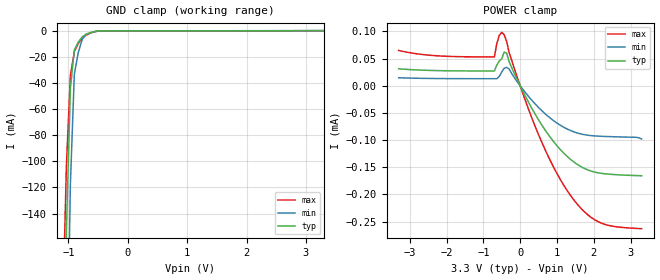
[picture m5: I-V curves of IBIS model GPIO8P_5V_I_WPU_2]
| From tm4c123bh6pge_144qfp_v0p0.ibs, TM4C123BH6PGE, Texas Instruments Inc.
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|   Model Cell GPIO8P_5V_I_WPU_2
[Model]   GPIO8P_5V_I_WPU_2
Model_type   Input
Polarity   Non-Inverting
Vinl =  0.8
Vinh =  2
C_comp   4.711578p   4.034737p   5.423069p
[Model Spec]
Vinl   0.8   0.8   0.8
Vinh   2   2   2
[Temperature Range]   25   125   -40
[Voltage Range]   3.3   2.97   3.63
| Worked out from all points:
|   GND clamp passes 1 mA (typ) near -0.58 V on its own axis
| Nom Voltages:
|   VDDC=1.2, VDD=3.3, GND=0
| Min Voltages:
|   VDDC=1.08, VDD=2.97, GND=0
| Max Voltages:
|   VDDC=1.32, VDD=3.63, GND=0
[POWER_clamp]
|   voltage   I(typ)   I(min)   I(max)
-3.3V     31.22uA    14.76uA    64.95uA
-700mV    27.24uA    13.03uA    53.12uA
-566.7mV  45.54uA    17.17uA    92.88uA
-500mV    49.58uA    25.46uA    98.23uA
-433.3mV  61.99uA    32.06uA    93.82uA
-366.7mV  60.27uA    33.88uA    81.56uA
-33.33mV  4.744uA    3.118uA    6.661uA
500mV     -62.72uA   -39.99uA   -89.98uA
900mV     -102.1uA   -63.88uA   -148.7uA
1.367V    -135.3uA   -82.34uA   -201.6uA
2.1V      -160uA     -92.63uA   -249.6uA
3.3V      -165.6uA   -97.93uA   -263uA
[GND_clamp]
|   voltage   I(typ)   I(min)   I(max)
-3.3V     -16.3A     -15.26A    -17.13A
-1.1V     -340.4mA   -570.5mA   -222.8mA
-1.033V   -152.7mA   -296.8mA   -103.3mA
-966.7mV  -44.18mA   -117.7mA   -34.41mA
-900mV    -14.77mA   -33.13mA   -16.15mA
-833.3mV  -8.769mA   -16.69mA   -9.878mA
-766.7mV  -4.756mA   -6.569mA   -5.651mA
-700mV    -2.732mA   -2.771mA   -3.471mA
-566.7mV  -805.7uA   -794.8uA   -943uA
-433.3mV  -213.6uA   -180.7uA   -296.9uA
3.3V      655.7pA    35.93uA    -61.41uA
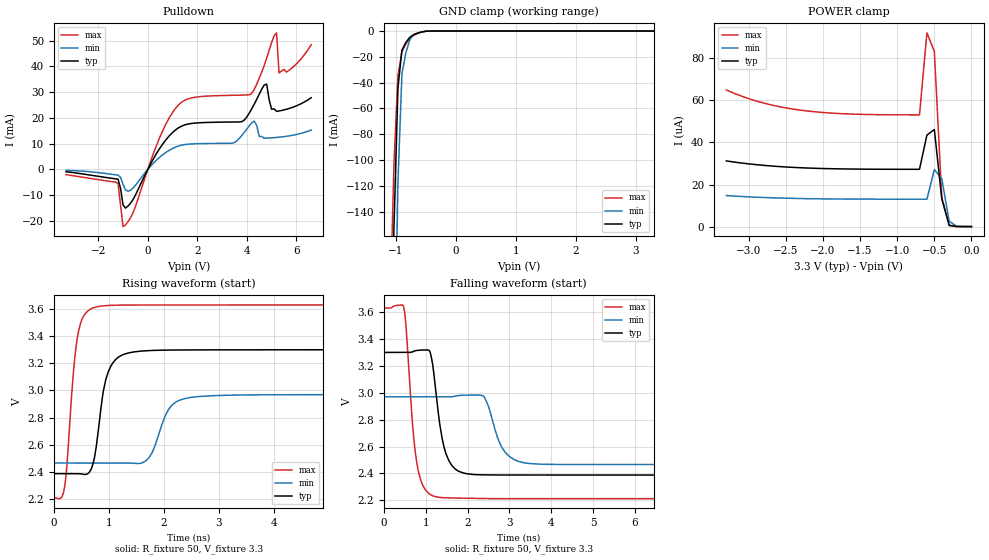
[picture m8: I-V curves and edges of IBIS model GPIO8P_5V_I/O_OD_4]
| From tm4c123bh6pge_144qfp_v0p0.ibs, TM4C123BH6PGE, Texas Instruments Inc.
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|   Model Cell GPIO8P_5V_I/O_OD_4
[Model]   GPIO8P_5V_I/O_OD_4
Model_type   I/O_open_drain
Polarity   Inverting
Enable   Active-Low
Vinl =  0.8
Vinh =  2
Cref =  15.0000pF
Rref =  100.0000M
Vref =  0V
Vmeas =  1.65
C_comp   4.711578p   4.034737p   5.423069p
[Model Spec]
Vinl   0.8   0.8   0.8
Vinh   2   2   2
[Temperature Range]   25   125   -40
[Voltage Range]   3.3   2.97   3.63
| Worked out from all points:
|   slope of the pulldown table from 0 to 0.495 V, typ, clamps not added: 59.3 ohm
|   GND clamp passes 1 mA (typ) near -0.59 V on its own axis
|   rising waveform, R_fixture 50, V_fixture 3.3: 20-80 % time 208ps typ, 290ps min, 166ps max; typ from 2.39 V to 3.3 V
|   falling waveform, R_fixture 50, V_fixture 3.3: 20-80 % time 259ps typ, 347ps min, 216ps max; typ from 3.3 V to 2.39 V
| Nom Voltages:
|   VDDC=1.2, VDD=3.3, GND=0
| Min Voltages:
|   VDDC=1.08, VDD=2.97, GND=0
| Max Voltages:
|   VDDC=1.32, VDD=3.63, GND=0
[POWER_clamp]
|   voltage   I(typ)   I(min)   I(max)
-3.3V     31.22uA    14.76uA    64.95uA
-3.1V     30.25uA    14.33uA    62.09uA
-2.8V     29.13uA    13.84uA    58.77uA
-2.3V     27.98uA    13.34uA    55.36uA
-1.7V     27.4uA     13.1uA     53.62uA
-700mV    27.24uA    13.03uA    53.12uA
-600mV    43.52uA    13.03uA    92.14uA
-500mV    46.16uA    27.05uA    83.3uA
-400mV    13.21uA    22.74uA    13.98uA
-300mV    630.7nA    2.501uA    480.9nA
-200mV    23.21nA    190.8nA    10.65nA
0V        660.4pA    10.19nA    564.9pA
[Pulldown]
|   voltage   I(typ)   I(min)   I(max)
-3.3V     -901.6uA   -384.4uA   -2.013mA
-1.2V     -3.786mA   -2.218mA   -5.418mA
-1V       -13.75mA   -5.79mA    -22.19mA
-700mV    -13.13mA   -8.08mA    -18.83mA
1.3V      16.5mA     9.253mA    25.59mA
3.5V      18.42mA    10.46mA    28.8mA
4.2V      23.61mA    18.14mA    29.55mA
4.8V      33.14mA    12.18mA    43.24mA
5V        23.36mA    12.28mA    49.33mA
5.2V      22.53mA    12.43mA    53.05mA
5.3V      22.7mA     12.52mA    37.48mA
6.6V      27.85mA    15.27mA    48.43mA
[GND_clamp]
|   voltage   I(typ)   I(min)   I(max)
-3.3V     -16.3A     -15.26A    -17.13A
-1.1V     -340.4mA   -570.5mA   -222.8mA
-1.033V   -152.7mA   -296.8mA   -103.3mA
-966.7mV  -44.18mA   -117.7mA   -34.4mA
-900mV    -14.77mA   -33.12mA   -16.14mA
-833.3mV  -8.752mA   -16.68mA   -9.833mA
-766.7mV  -4.716mA   -6.551mA   -5.563mA
-700mV    -2.657mA   -2.741mA   -3.333mA
-566.7mV  -672.8uA   -727.2uA   -724.4uA
-433.3mV  -51.87uA   -90.8uA    -37.79uA
3.3V      660.4pA    5.308uA    422.7pA
[Ramp]
| variable   typ   min   max
dV/dt_f  0.5587141/0.26045662n 0.31023858/0.352185n  0.86504244/0.21760119n
dV/dt_r 0.72667108/0.52198411n 0.45768162/0.8533017n   1.027789/0.38356156n
R_load = 50
[Rising Waveform]
R_fixture = 50
V_fixture = 3.3
V_fixture_min = 2.97
V_fixture_max = 3.63
|   time   V(typ)   V(min)   V(max)
0s        2.388V     2.466V     2.211V
198.6ps   2.388V     2.466V     2.297V
375ps     2.388V     2.466V     3.219V
457.4ps   2.387V     2.466V     3.451V
692.2ps   2.433V     2.466V     3.604V
849.4ps   2.842V     2.466V     3.621V
982.8ps   3.13V      2.466V     3.626V
1.222ns   3.257V     2.466V     3.629V
2.761ns   3.299V     2.959V     3.63V
20.01ns   3.3V       2.97V      3.63V
[Falling Waveform]
R_fixture = 50
V_fixture = 3.3
V_fixture_min = 2.97
V_fixture_max = 3.63
|   time   V(typ)   V(min)   V(max)
0s        3.3V       2.97V      3.63V
471.4ps   3.3V       2.97V      3.639V
817.4ps   3.316V     2.97V      2.422V
1.099ns   3.305V     2.97V      2.245V
1.273ns   2.918V     2.97V      2.224V
1.545ns   2.499V     2.97V      2.218V
2.126ns   2.392V     2.982V     2.214V
2.889ns   2.388V     2.56V      2.212V
3.475ns   2.388V     2.474V     2.212V
20.01ns   2.388V     2.466V     2.212V
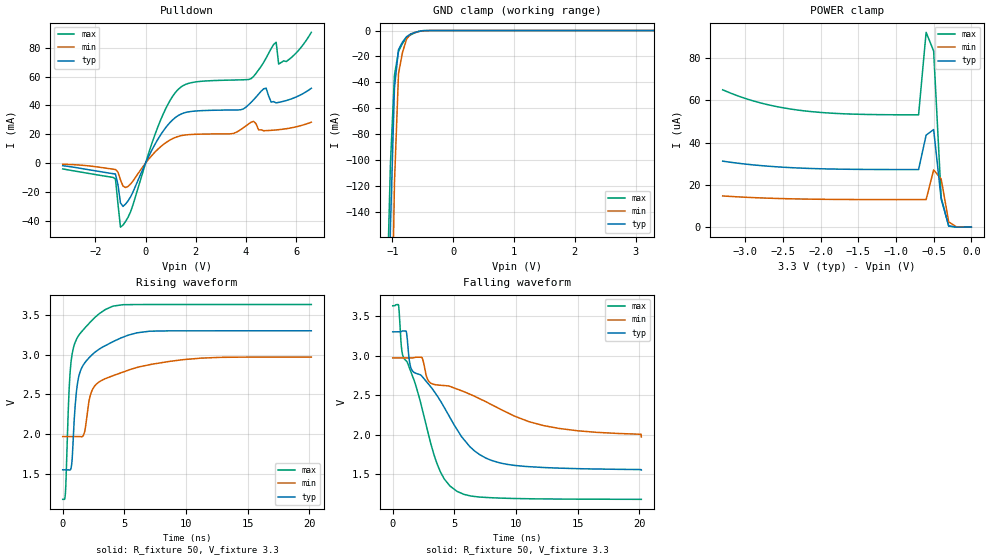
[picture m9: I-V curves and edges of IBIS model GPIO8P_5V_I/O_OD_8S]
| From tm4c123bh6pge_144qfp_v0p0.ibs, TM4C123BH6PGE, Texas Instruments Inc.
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|   Model Cell GPIO8P_5V_I/O_OD_8S
[Model]   GPIO8P_5V_I/O_OD_8S
Model_type   I/O_open_drain
Polarity   Inverting
Enable   Active-Low
Vinl =  0.8
Vinh =  2
Cref =  15.0000pF
Rref =  100.0000M
Vref =  0V
Vmeas =  1.65
C_comp   4.711578p   4.034737p   5.423069p
[Model Spec]
Vinl   0.8   0.8   0.8
Vinh   2   2   2
[Temperature Range]   25   125   -40
[Voltage Range]   3.3   2.97   3.63
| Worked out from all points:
|   slope of the pulldown table from 0 to 0.495 V, typ, clamps not added: 29.7 ohm
|   GND clamp passes 1 mA (typ) near -0.59 V on its own axis
|   rising waveform, R_fixture 50, V_fixture 3.3: 20-80 % time 1.23ns typ, 2.77ns min, 657ps max; typ from 1.55 V to 3.3 V
|   falling waveform, R_fixture 50, V_fixture 3.3: 20-80 % time 4.63ns typ, 8.26ns min, 2.82ns max; typ from 3.3 V to 1.55 V
| Nom Voltages:
|   VDDC=1.2, VDD=3.3, GND=0
| Min Voltages:
|   VDDC=1.08, VDD=2.97, GND=0
| Max Voltages:
|   VDDC=1.32, VDD=3.63, GND=0
[POWER_clamp]
|   voltage   I(typ)   I(min)   I(max)
-3.3V     31.22uA    14.76uA    64.95uA
-3.1V     30.25uA    14.33uA    62.09uA
-2.8V     29.13uA    13.84uA    58.77uA
-2.3V     27.98uA    13.34uA    55.36uA
-1.7V     27.4uA     13.1uA     53.62uA
-700mV    27.24uA    13.03uA    53.12uA
-600mV    43.52uA    13.03uA    92.14uA
-500mV    46.16uA    27.05uA    83.3uA
-400mV    13.21uA    22.74uA    13.98uA
-300mV    630.7nA    2.501uA    480.9nA
-200mV    23.21nA    190.8nA    10.65nA
0V        660.3pA    10.19nA    564.9pA
[Pulldown]
|   voltage   I(typ)   I(min)   I(max)
-3.3V     -1.804mA   -768.9uA   -4.029mA
-1.2V     -7.576mA   -4.438mA   -10.94mA
-1V       -27.56mA   -11.61mA   -44.39mA
-700mV    -26.23mA   -16.15mA   -37.6mA
500mV     16.83mA    9.794mA    25.59mA
1.3V      32.99mA    18.5mA     51.14mA
3.5V      36.85mA    20.6mA     57.6mA
4.2V      42.1mA     28.33mA    58.55mA
4.8V      51.96mA    22.52mA    72.86mA
5.2V      41.77mA    23mA       83.78mA
5.3V      42.1mA     23.17mA    68.63mA
6.6V      51.87mA    28.39mA    90.67mA
[GND_clamp]
|   voltage   I(typ)   I(min)   I(max)
-3.3V     -16.3A     -15.26A    -17.13A
-1.1V     -340.4mA   -570.5mA   -222.8mA
-1.033V   -152.7mA   -296.8mA   -103.3mA
-966.7mV  -44.18mA   -117.7mA   -34.4mA
-900mV    -14.77mA   -33.12mA   -16.14mA
-833.3mV  -8.752mA   -16.68mA   -9.833mA
-766.7mV  -4.716mA   -6.551mA   -5.563mA
-700mV    -2.657mA   -2.741mA   -3.333mA
-566.7mV  -672.8uA   -727.2uA   -724.4uA
-433.3mV  -51.87uA   -90.8uA    -37.79uA
3.3V      660.3pA    5.308uA    422.7pA
[Ramp]
| variable   typ   min   max
dV/dt_f  1.0557963/4.6216941n 0.60488119/8.2398767n  1.4782959/2.8219071n
dV/dt_r  1.1075872/4.4039012n 0.75620404/9.0634394n  1.4663476/2.6218461n
R_load = 50
[Rising Waveform]
R_fixture = 50
V_fixture = 3.3
V_fixture_min = 2.97
V_fixture_max = 3.63
|   time   V(typ)   V(min)   V(max)
0s        1.553V     1.971V     1.182V
219.8ps   1.553V     1.971V     1.259V
549.8ps   1.55V      1.971V     2.656V
813.3ps   1.809V     1.971V     3.049V
1.018ns   2.375V     1.971V     3.158V
1.326ns   2.741V     1.971V     3.248V
1.727ns   2.884V     2.004V     3.323V
2.94ns    3.067V     2.656V     3.512V
7.005ns   3.294V     2.873V     3.63V
20.16ns   3.3V       2.97V      3.63V
[Falling Waveform]
R_fixture = 50
V_fixture = 3.3
V_fixture_min = 2.97
V_fixture_max = 3.63
|   time   V(typ)   V(min)   V(max)
0s        3.3V       2.97V      3.63V
473.3ps   3.3V       2.97V      3.639V
717.3ps   3.307V     2.97V      3.089V
1.083ns   3.31V      2.97V      2.936V
1.501ns   2.834V     2.97V      2.79V
2.371ns   2.739V     2.975V     2.336V
3.475ns   2.522V     2.631V     1.686V
4.628ns   2.221V     2.611V     1.353V
8.542ns   1.649V     2.337V     1.199V
20.16ns   1.553V     1.971V     1.182V
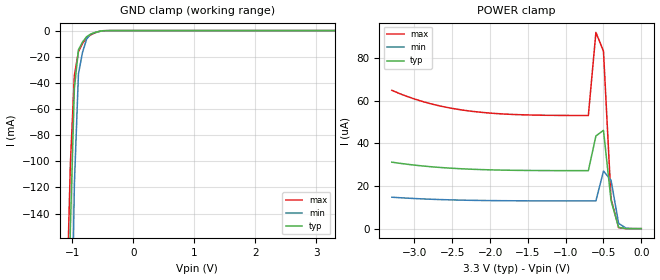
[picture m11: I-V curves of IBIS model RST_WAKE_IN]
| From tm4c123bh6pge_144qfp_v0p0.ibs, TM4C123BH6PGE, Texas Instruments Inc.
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|   Model Cell RST_WAKE_IN
[Model]   RST_WAKE_IN
Model_type   Input
Polarity   Non-Inverting
Vinl =  0.8
Vinh =  2
C_comp   4.711578p   4.034737p   5.423069p
[Model Spec]
Vinl   0.8   0.8   0.8
Vinh   2   2   2
[Temperature Range]   25   125   -40
[Voltage Range]   3.3   2.97   3.63
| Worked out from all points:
|   GND clamp passes 1 mA (typ) near -0.59 V on its own axis
| Nom Voltages:
|   VDDC=1.2, VDD=3.3, GND=0
| Min Voltages:
|   VDDC=1.08, VDD=2.97, GND=0
| Max Voltages:
|   VDDC=1.32, VDD=3.63, GND=0
[POWER_clamp]
|   voltage   I(typ)   I(min)   I(max)
-3.3V     31.22uA    14.76uA    64.95uA
-3.1V     30.25uA    14.33uA    62.09uA
-2.8V     29.13uA    13.84uA    58.77uA
-2.3V     27.98uA    13.34uA    55.36uA
-1.7V     27.4uA     13.1uA     53.62uA
-700mV    27.24uA    13.03uA    53.12uA
-600mV    43.52uA    13.03uA    92.14uA
-500mV    46.16uA    27.05uA    83.3uA
-400mV    13.21uA    22.74uA    13.98uA
-300mV    630.7nA    2.501uA    480.9nA
-200mV    23.21nA    190.8nA    10.65nA
0V        660.4pA    10.19nA    564.9pA
[GND_clamp]
|   voltage   I(typ)   I(min)   I(max)
-3.3V     -16.3A     -15.26A    -17.13A
-1.1V     -340.4mA   -570.5mA   -222.8mA
-1.033V   -152.7mA   -296.8mA   -103.3mA
-966.7mV  -44.18mA   -117.7mA   -34.4mA
-900mV    -14.77mA   -33.12mA   -16.14mA
-833.3mV  -8.752mA   -16.68mA   -9.833mA
-766.7mV  -4.716mA   -6.551mA   -5.563mA
-700mV    -2.657mA   -2.741mA   -3.333mA
-566.7mV  -672.8uA   -727.2uA   -724.4uA
-433.3mV  -51.87uA   -90.8uA    -37.79uA
3.3V      660.4pA    5.308uA    422.7pA
